VERSION 5.8 ;
BUSBITCHARS "[]" ;
DIVIDERCHAR "/" ;
UNITS
    DATABASE MICRONS 1000 ;
END UNITS

VIA simple_alu_via2_3_1600_480_1_5_320_320
  VIARULE M1M2_PR ;
  CUTSIZE 0.15 0.15 ;
  LAYERS met1 via met2 ;
  CUTSPACING 0.17 0.17 ;
  ENCLOSURE 0.085 0.165 0.055 0.085 ;
  ROWCOL 1 5 ;
END simple_alu_via2_3_1600_480_1_5_320_320

VIA simple_alu_via3_4_1600_480_1_4_400_400
  VIARULE M2M3_PR ;
  CUTSIZE 0.2 0.2 ;
  LAYERS met2 via2 met3 ;
  CUTSPACING 0.2 0.2 ;
  ENCLOSURE 0.04 0.085 0.065 0.065 ;
  ROWCOL 1 4 ;
END simple_alu_via3_4_1600_480_1_4_400_400

VIA simple_alu_via4_5_1600_480_1_4_400_400
  VIARULE M3M4_PR ;
  CUTSIZE 0.2 0.2 ;
  LAYERS met3 via3 met4 ;
  CUTSPACING 0.2 0.2 ;
  ENCLOSURE 0.09 0.06 0.1 0.065 ;
  ROWCOL 1 4 ;
END simple_alu_via4_5_1600_480_1_4_400_400

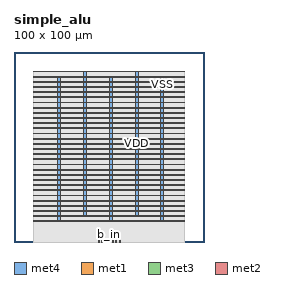
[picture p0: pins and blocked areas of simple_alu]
MACRO simple_alu
  FOREIGN simple_alu 0 0 ;
  CLASS BLOCK ;
  SIZE 100 BY 100 ;
  PIN VDD
    USE POWER ;
    DIRECTION INOUT ;
    PORT
      LAYER met4 ;
        RECT  63.72 13.36 65.32 90 ;
        RECT  36.52 13.36 38.12 90 ;
      LAYER met1 ;
        RECT  10.12 89.52 89.7 90 ;
        RECT  10.12 84.08 89.7 84.56 ;
        RECT  10.12 78.64 89.7 79.12 ;
        RECT  10.12 73.2 89.7 73.68 ;
        RECT  10.12 67.76 89.7 68.24 ;
        RECT  10.12 62.32 89.7 62.8 ;
        RECT  10.12 56.88 89.7 57.36 ;
        RECT  10.12 51.44 89.7 51.92 ;
        RECT  10.12 46 89.7 46.48 ;
        RECT  10.12 40.56 89.7 41.04 ;
        RECT  10.12 35.12 89.7 35.6 ;
        RECT  10.12 29.68 89.7 30.16 ;
        RECT  10.12 24.24 89.7 24.72 ;
        RECT  10.12 18.8 89.7 19.28 ;
        RECT  10.12 13.36 89.7 13.84 ;
      LAYER met3 ;
        RECT  63.73 89.595 65.31 89.925 ;
      VIA 64.52 89.76 simple_alu_via4_5_1600_480_1_4_400_400 ;
      LAYER met2 ;
        RECT  63.75 89.575 65.29 89.945 ;
      VIA 64.52 89.76 simple_alu_via3_4_1600_480_1_4_400_400 ;
      VIA 64.52 89.76 simple_alu_via2_3_1600_480_1_5_320_320 ;
      LAYER met3 ;
        RECT  63.73 84.155 65.31 84.485 ;
      VIA 64.52 84.32 simple_alu_via4_5_1600_480_1_4_400_400 ;
      LAYER met2 ;
        RECT  63.75 84.135 65.29 84.505 ;
      VIA 64.52 84.32 simple_alu_via3_4_1600_480_1_4_400_400 ;
      VIA 64.52 84.32 simple_alu_via2_3_1600_480_1_5_320_320 ;
      LAYER met3 ;
        RECT  63.73 78.715 65.31 79.045 ;
      VIA 64.52 78.88 simple_alu_via4_5_1600_480_1_4_400_400 ;
      LAYER met2 ;
        RECT  63.75 78.695 65.29 79.065 ;
      VIA 64.52 78.88 simple_alu_via3_4_1600_480_1_4_400_400 ;
      VIA 64.52 78.88 simple_alu_via2_3_1600_480_1_5_320_320 ;
      LAYER met3 ;
        RECT  63.73 73.275 65.31 73.605 ;
      VIA 64.52 73.44 simple_alu_via4_5_1600_480_1_4_400_400 ;
      LAYER met2 ;
        RECT  63.75 73.255 65.29 73.625 ;
      VIA 64.52 73.44 simple_alu_via3_4_1600_480_1_4_400_400 ;
      VIA 64.52 73.44 simple_alu_via2_3_1600_480_1_5_320_320 ;
      LAYER met3 ;
        RECT  63.73 67.835 65.31 68.165 ;
      VIA 64.52 68 simple_alu_via4_5_1600_480_1_4_400_400 ;
      LAYER met2 ;
        RECT  63.75 67.815 65.29 68.185 ;
      VIA 64.52 68 simple_alu_via3_4_1600_480_1_4_400_400 ;
      VIA 64.52 68 simple_alu_via2_3_1600_480_1_5_320_320 ;
      LAYER met3 ;
        RECT  63.73 62.395 65.31 62.725 ;
      VIA 64.52 62.56 simple_alu_via4_5_1600_480_1_4_400_400 ;
      LAYER met2 ;
        RECT  63.75 62.375 65.29 62.745 ;
      VIA 64.52 62.56 simple_alu_via3_4_1600_480_1_4_400_400 ;
      VIA 64.52 62.56 simple_alu_via2_3_1600_480_1_5_320_320 ;
      LAYER met3 ;
        RECT  63.73 56.955 65.31 57.285 ;
      VIA 64.52 57.12 simple_alu_via4_5_1600_480_1_4_400_400 ;
      LAYER met2 ;
        RECT  63.75 56.935 65.29 57.305 ;
      VIA 64.52 57.12 simple_alu_via3_4_1600_480_1_4_400_400 ;
      VIA 64.52 57.12 simple_alu_via2_3_1600_480_1_5_320_320 ;
      LAYER met3 ;
        RECT  63.73 51.515 65.31 51.845 ;
      VIA 64.52 51.68 simple_alu_via4_5_1600_480_1_4_400_400 ;
      LAYER met2 ;
        RECT  63.75 51.495 65.29 51.865 ;
      VIA 64.52 51.68 simple_alu_via3_4_1600_480_1_4_400_400 ;
      VIA 64.52 51.68 simple_alu_via2_3_1600_480_1_5_320_320 ;
      LAYER met3 ;
        RECT  63.73 46.075 65.31 46.405 ;
      VIA 64.52 46.24 simple_alu_via4_5_1600_480_1_4_400_400 ;
      LAYER met2 ;
        RECT  63.75 46.055 65.29 46.425 ;
      VIA 64.52 46.24 simple_alu_via3_4_1600_480_1_4_400_400 ;
      VIA 64.52 46.24 simple_alu_via2_3_1600_480_1_5_320_320 ;
      LAYER met3 ;
        RECT  63.73 40.635 65.31 40.965 ;
      VIA 64.52 40.8 simple_alu_via4_5_1600_480_1_4_400_400 ;
      LAYER met2 ;
        RECT  63.75 40.615 65.29 40.985 ;
      VIA 64.52 40.8 simple_alu_via3_4_1600_480_1_4_400_400 ;
      VIA 64.52 40.8 simple_alu_via2_3_1600_480_1_5_320_320 ;
      LAYER met3 ;
        RECT  63.73 35.195 65.31 35.525 ;
      VIA 64.52 35.36 simple_alu_via4_5_1600_480_1_4_400_400 ;
      LAYER met2 ;
        RECT  63.75 35.175 65.29 35.545 ;
      VIA 64.52 35.36 simple_alu_via3_4_1600_480_1_4_400_400 ;
      VIA 64.52 35.36 simple_alu_via2_3_1600_480_1_5_320_320 ;
      LAYER met3 ;
        RECT  63.73 29.755 65.31 30.085 ;
      VIA 64.52 29.92 simple_alu_via4_5_1600_480_1_4_400_400 ;
      LAYER met2 ;
        RECT  63.75 29.735 65.29 30.105 ;
      VIA 64.52 29.92 simple_alu_via3_4_1600_480_1_4_400_400 ;
      VIA 64.52 29.92 simple_alu_via2_3_1600_480_1_5_320_320 ;
      LAYER met3 ;
        RECT  63.73 24.315 65.31 24.645 ;
      VIA 64.52 24.48 simple_alu_via4_5_1600_480_1_4_400_400 ;
      LAYER met2 ;
        RECT  63.75 24.295 65.29 24.665 ;
      VIA 64.52 24.48 simple_alu_via3_4_1600_480_1_4_400_400 ;
      VIA 64.52 24.48 simple_alu_via2_3_1600_480_1_5_320_320 ;
      LAYER met3 ;
        RECT  63.73 18.875 65.31 19.205 ;
      VIA 64.52 19.04 simple_alu_via4_5_1600_480_1_4_400_400 ;
      LAYER met2 ;
        RECT  63.75 18.855 65.29 19.225 ;
      VIA 64.52 19.04 simple_alu_via3_4_1600_480_1_4_400_400 ;
      VIA 64.52 19.04 simple_alu_via2_3_1600_480_1_5_320_320 ;
      LAYER met3 ;
        RECT  63.73 13.435 65.31 13.765 ;
      VIA 64.52 13.6 simple_alu_via4_5_1600_480_1_4_400_400 ;
      LAYER met2 ;
        RECT  63.75 13.415 65.29 13.785 ;
      VIA 64.52 13.6 simple_alu_via3_4_1600_480_1_4_400_400 ;
      VIA 64.52 13.6 simple_alu_via2_3_1600_480_1_5_320_320 ;
      LAYER met3 ;
        RECT  36.53 89.595 38.11 89.925 ;
      VIA 37.32 89.76 simple_alu_via4_5_1600_480_1_4_400_400 ;
      LAYER met2 ;
        RECT  36.55 89.575 38.09 89.945 ;
      VIA 37.32 89.76 simple_alu_via3_4_1600_480_1_4_400_400 ;
      VIA 37.32 89.76 simple_alu_via2_3_1600_480_1_5_320_320 ;
      LAYER met3 ;
        RECT  36.53 84.155 38.11 84.485 ;
      VIA 37.32 84.32 simple_alu_via4_5_1600_480_1_4_400_400 ;
      LAYER met2 ;
        RECT  36.55 84.135 38.09 84.505 ;
      VIA 37.32 84.32 simple_alu_via3_4_1600_480_1_4_400_400 ;
      VIA 37.32 84.32 simple_alu_via2_3_1600_480_1_5_320_320 ;
      LAYER met3 ;
        RECT  36.53 78.715 38.11 79.045 ;
      VIA 37.32 78.88 simple_alu_via4_5_1600_480_1_4_400_400 ;
      LAYER met2 ;
        RECT  36.55 78.695 38.09 79.065 ;
      VIA 37.32 78.88 simple_alu_via3_4_1600_480_1_4_400_400 ;
      VIA 37.32 78.88 simple_alu_via2_3_1600_480_1_5_320_320 ;
      LAYER met3 ;
        RECT  36.53 73.275 38.11 73.605 ;
      VIA 37.32 73.44 simple_alu_via4_5_1600_480_1_4_400_400 ;
      LAYER met2 ;
        RECT  36.55 73.255 38.09 73.625 ;
      VIA 37.32 73.44 simple_alu_via3_4_1600_480_1_4_400_400 ;
      VIA 37.32 73.44 simple_alu_via2_3_1600_480_1_5_320_320 ;
      LAYER met3 ;
        RECT  36.53 67.835 38.11 68.165 ;
      VIA 37.32 68 simple_alu_via4_5_1600_480_1_4_400_400 ;
      LAYER met2 ;
        RECT  36.55 67.815 38.09 68.185 ;
      VIA 37.32 68 simple_alu_via3_4_1600_480_1_4_400_400 ;
      VIA 37.32 68 simple_alu_via2_3_1600_480_1_5_320_320 ;
      LAYER met3 ;
        RECT  36.53 62.395 38.11 62.725 ;
      VIA 37.32 62.56 simple_alu_via4_5_1600_480_1_4_400_400 ;
      LAYER met2 ;
        RECT  36.55 62.375 38.09 62.745 ;
      VIA 37.32 62.56 simple_alu_via3_4_1600_480_1_4_400_400 ;
      VIA 37.32 62.56 simple_alu_via2_3_1600_480_1_5_320_320 ;
      LAYER met3 ;
        RECT  36.53 56.955 38.11 57.285 ;
      VIA 37.32 57.12 simple_alu_via4_5_1600_480_1_4_400_400 ;
      LAYER met2 ;
        RECT  36.55 56.935 38.09 57.305 ;
      VIA 37.32 57.12 simple_alu_via3_4_1600_480_1_4_400_400 ;
      VIA 37.32 57.12 simple_alu_via2_3_1600_480_1_5_320_320 ;
      LAYER met3 ;
        RECT  36.53 51.515 38.11 51.845 ;
      VIA 37.32 51.68 simple_alu_via4_5_1600_480_1_4_400_400 ;
      LAYER met2 ;
        RECT  36.55 51.495 38.09 51.865 ;
      VIA 37.32 51.68 simple_alu_via3_4_1600_480_1_4_400_400 ;
      VIA 37.32 51.68 simple_alu_via2_3_1600_480_1_5_320_320 ;
      LAYER met3 ;
        RECT  36.53 46.075 38.11 46.405 ;
      VIA 37.32 46.24 simple_alu_via4_5_1600_480_1_4_400_400 ;
      LAYER met2 ;
        RECT  36.55 46.055 38.09 46.425 ;
      VIA 37.32 46.24 simple_alu_via3_4_1600_480_1_4_400_400 ;
      VIA 37.32 46.24 simple_alu_via2_3_1600_480_1_5_320_320 ;
      LAYER met3 ;
        RECT  36.53 40.635 38.11 40.965 ;
      VIA 37.32 40.8 simple_alu_via4_5_1600_480_1_4_400_400 ;
      LAYER met2 ;
        RECT  36.55 40.615 38.09 40.985 ;
      VIA 37.32 40.8 simple_alu_via3_4_1600_480_1_4_400_400 ;
      VIA 37.32 40.8 simple_alu_via2_3_1600_480_1_5_320_320 ;
      LAYER met3 ;
        RECT  36.53 35.195 38.11 35.525 ;
      VIA 37.32 35.36 simple_alu_via4_5_1600_480_1_4_400_400 ;
      LAYER met2 ;
        RECT  36.55 35.175 38.09 35.545 ;
      VIA 37.32 35.36 simple_alu_via3_4_1600_480_1_4_400_400 ;
      VIA 37.32 35.36 simple_alu_via2_3_1600_480_1_5_320_320 ;
      LAYER met3 ;
        RECT  36.53 29.755 38.11 30.085 ;
      VIA 37.32 29.92 simple_alu_via4_5_1600_480_1_4_400_400 ;
      LAYER met2 ;
        RECT  36.55 29.735 38.09 30.105 ;
      VIA 37.32 29.92 simple_alu_via3_4_1600_480_1_4_400_400 ;
      VIA 37.32 29.92 simple_alu_via2_3_1600_480_1_5_320_320 ;
      LAYER met3 ;
        RECT  36.53 24.315 38.11 24.645 ;
      VIA 37.32 24.48 simple_alu_via4_5_1600_480_1_4_400_400 ;
      LAYER met2 ;
        RECT  36.55 24.295 38.09 24.665 ;
      VIA 37.32 24.48 simple_alu_via3_4_1600_480_1_4_400_400 ;
      VIA 37.32 24.48 simple_alu_via2_3_1600_480_1_5_320_320 ;
      LAYER met3 ;
        RECT  36.53 18.875 38.11 19.205 ;
      VIA 37.32 19.04 simple_alu_via4_5_1600_480_1_4_400_400 ;
      LAYER met2 ;
        RECT  36.55 18.855 38.09 19.225 ;
      VIA 37.32 19.04 simple_alu_via3_4_1600_480_1_4_400_400 ;
      VIA 37.32 19.04 simple_alu_via2_3_1600_480_1_5_320_320 ;
      LAYER met3 ;
        RECT  36.53 13.435 38.11 13.765 ;
      VIA 37.32 13.6 simple_alu_via4_5_1600_480_1_4_400_400 ;
      LAYER met2 ;
        RECT  36.55 13.415 38.09 13.785 ;
      VIA 37.32 13.6 simple_alu_via3_4_1600_480_1_4_400_400 ;
      VIA 37.32 13.6 simple_alu_via2_3_1600_480_1_5_320_320 ;
    END
  END VDD
  PIN VSS
    USE GROUND ;
    DIRECTION INOUT ;
    PORT
      LAYER met4 ;
        RECT  77.32 10.64 78.92 87.28 ;
        RECT  50.12 10.64 51.72 87.28 ;
        RECT  22.92 10.64 24.52 87.28 ;
      LAYER met1 ;
        RECT  10.12 86.8 89.7 87.28 ;
        RECT  10.12 81.36 89.7 81.84 ;
        RECT  10.12 75.92 89.7 76.4 ;
        RECT  10.12 70.48 89.7 70.96 ;
        RECT  10.12 65.04 89.7 65.52 ;
        RECT  10.12 59.6 89.7 60.08 ;
        RECT  10.12 54.16 89.7 54.64 ;
        RECT  10.12 48.72 89.7 49.2 ;
        RECT  10.12 43.28 89.7 43.76 ;
        RECT  10.12 37.84 89.7 38.32 ;
        RECT  10.12 32.4 89.7 32.88 ;
        RECT  10.12 26.96 89.7 27.44 ;
        RECT  10.12 21.52 89.7 22 ;
        RECT  10.12 16.08 89.7 16.56 ;
        RECT  10.12 10.64 89.7 11.12 ;
      LAYER met3 ;
        RECT  77.33 86.875 78.91 87.205 ;
      VIA 78.12 87.04 simple_alu_via4_5_1600_480_1_4_400_400 ;
      LAYER met2 ;
        RECT  77.35 86.855 78.89 87.225 ;
      VIA 78.12 87.04 simple_alu_via3_4_1600_480_1_4_400_400 ;
      VIA 78.12 87.04 simple_alu_via2_3_1600_480_1_5_320_320 ;
      LAYER met3 ;
        RECT  77.33 81.435 78.91 81.765 ;
      VIA 78.12 81.6 simple_alu_via4_5_1600_480_1_4_400_400 ;
      LAYER met2 ;
        RECT  77.35 81.415 78.89 81.785 ;
      VIA 78.12 81.6 simple_alu_via3_4_1600_480_1_4_400_400 ;
      VIA 78.12 81.6 simple_alu_via2_3_1600_480_1_5_320_320 ;
      LAYER met3 ;
        RECT  77.33 75.995 78.91 76.325 ;
      VIA 78.12 76.16 simple_alu_via4_5_1600_480_1_4_400_400 ;
      LAYER met2 ;
        RECT  77.35 75.975 78.89 76.345 ;
      VIA 78.12 76.16 simple_alu_via3_4_1600_480_1_4_400_400 ;
      VIA 78.12 76.16 simple_alu_via2_3_1600_480_1_5_320_320 ;
      LAYER met3 ;
        RECT  77.33 70.555 78.91 70.885 ;
      VIA 78.12 70.72 simple_alu_via4_5_1600_480_1_4_400_400 ;
      LAYER met2 ;
        RECT  77.35 70.535 78.89 70.905 ;
      VIA 78.12 70.72 simple_alu_via3_4_1600_480_1_4_400_400 ;
      VIA 78.12 70.72 simple_alu_via2_3_1600_480_1_5_320_320 ;
      LAYER met3 ;
        RECT  77.33 65.115 78.91 65.445 ;
      VIA 78.12 65.28 simple_alu_via4_5_1600_480_1_4_400_400 ;
      LAYER met2 ;
        RECT  77.35 65.095 78.89 65.465 ;
      VIA 78.12 65.28 simple_alu_via3_4_1600_480_1_4_400_400 ;
      VIA 78.12 65.28 simple_alu_via2_3_1600_480_1_5_320_320 ;
      LAYER met3 ;
        RECT  77.33 59.675 78.91 60.005 ;
      VIA 78.12 59.84 simple_alu_via4_5_1600_480_1_4_400_400 ;
      LAYER met2 ;
        RECT  77.35 59.655 78.89 60.025 ;
      VIA 78.12 59.84 simple_alu_via3_4_1600_480_1_4_400_400 ;
      VIA 78.12 59.84 simple_alu_via2_3_1600_480_1_5_320_320 ;
      LAYER met3 ;
        RECT  77.33 54.235 78.91 54.565 ;
      VIA 78.12 54.4 simple_alu_via4_5_1600_480_1_4_400_400 ;
      LAYER met2 ;
        RECT  77.35 54.215 78.89 54.585 ;
      VIA 78.12 54.4 simple_alu_via3_4_1600_480_1_4_400_400 ;
      VIA 78.12 54.4 simple_alu_via2_3_1600_480_1_5_320_320 ;
      LAYER met3 ;
        RECT  77.33 48.795 78.91 49.125 ;
      VIA 78.12 48.96 simple_alu_via4_5_1600_480_1_4_400_400 ;
      LAYER met2 ;
        RECT  77.35 48.775 78.89 49.145 ;
      VIA 78.12 48.96 simple_alu_via3_4_1600_480_1_4_400_400 ;
      VIA 78.12 48.96 simple_alu_via2_3_1600_480_1_5_320_320 ;
      LAYER met3 ;
        RECT  77.33 43.355 78.91 43.685 ;
      VIA 78.12 43.52 simple_alu_via4_5_1600_480_1_4_400_400 ;
      LAYER met2 ;
        RECT  77.35 43.335 78.89 43.705 ;
      VIA 78.12 43.52 simple_alu_via3_4_1600_480_1_4_400_400 ;
      VIA 78.12 43.52 simple_alu_via2_3_1600_480_1_5_320_320 ;
      LAYER met3 ;
        RECT  77.33 37.915 78.91 38.245 ;
      VIA 78.12 38.08 simple_alu_via4_5_1600_480_1_4_400_400 ;
      LAYER met2 ;
        RECT  77.35 37.895 78.89 38.265 ;
      VIA 78.12 38.08 simple_alu_via3_4_1600_480_1_4_400_400 ;
      VIA 78.12 38.08 simple_alu_via2_3_1600_480_1_5_320_320 ;
      LAYER met3 ;
        RECT  77.33 32.475 78.91 32.805 ;
      VIA 78.12 32.64 simple_alu_via4_5_1600_480_1_4_400_400 ;
      LAYER met2 ;
        RECT  77.35 32.455 78.89 32.825 ;
      VIA 78.12 32.64 simple_alu_via3_4_1600_480_1_4_400_400 ;
      VIA 78.12 32.64 simple_alu_via2_3_1600_480_1_5_320_320 ;
      LAYER met3 ;
        RECT  77.33 27.035 78.91 27.365 ;
      VIA 78.12 27.2 simple_alu_via4_5_1600_480_1_4_400_400 ;
      LAYER met2 ;
        RECT  77.35 27.015 78.89 27.385 ;
      VIA 78.12 27.2 simple_alu_via3_4_1600_480_1_4_400_400 ;
      VIA 78.12 27.2 simple_alu_via2_3_1600_480_1_5_320_320 ;
      LAYER met3 ;
        RECT  77.33 21.595 78.91 21.925 ;
      VIA 78.12 21.76 simple_alu_via4_5_1600_480_1_4_400_400 ;
      LAYER met2 ;
        RECT  77.35 21.575 78.89 21.945 ;
      VIA 78.12 21.76 simple_alu_via3_4_1600_480_1_4_400_400 ;
      VIA 78.12 21.76 simple_alu_via2_3_1600_480_1_5_320_320 ;
      LAYER met3 ;
        RECT  77.33 16.155 78.91 16.485 ;
      VIA 78.12 16.32 simple_alu_via4_5_1600_480_1_4_400_400 ;
      LAYER met2 ;
        RECT  77.35 16.135 78.89 16.505 ;
      VIA 78.12 16.32 simple_alu_via3_4_1600_480_1_4_400_400 ;
      VIA 78.12 16.32 simple_alu_via2_3_1600_480_1_5_320_320 ;
      LAYER met3 ;
        RECT  77.33 10.715 78.91 11.045 ;
      VIA 78.12 10.88 simple_alu_via4_5_1600_480_1_4_400_400 ;
      LAYER met2 ;
        RECT  77.35 10.695 78.89 11.065 ;
      VIA 78.12 10.88 simple_alu_via3_4_1600_480_1_4_400_400 ;
      VIA 78.12 10.88 simple_alu_via2_3_1600_480_1_5_320_320 ;
      LAYER met3 ;
        RECT  50.13 86.875 51.71 87.205 ;
      VIA 50.92 87.04 simple_alu_via4_5_1600_480_1_4_400_400 ;
      LAYER met2 ;
        RECT  50.15 86.855 51.69 87.225 ;
      VIA 50.92 87.04 simple_alu_via3_4_1600_480_1_4_400_400 ;
      VIA 50.92 87.04 simple_alu_via2_3_1600_480_1_5_320_320 ;
      LAYER met3 ;
        RECT  50.13 81.435 51.71 81.765 ;
      VIA 50.92 81.6 simple_alu_via4_5_1600_480_1_4_400_400 ;
      LAYER met2 ;
        RECT  50.15 81.415 51.69 81.785 ;
      VIA 50.92 81.6 simple_alu_via3_4_1600_480_1_4_400_400 ;
      VIA 50.92 81.6 simple_alu_via2_3_1600_480_1_5_320_320 ;
      LAYER met3 ;
        RECT  50.13 75.995 51.71 76.325 ;
      VIA 50.92 76.16 simple_alu_via4_5_1600_480_1_4_400_400 ;
      LAYER met2 ;
        RECT  50.15 75.975 51.69 76.345 ;
      VIA 50.92 76.16 simple_alu_via3_4_1600_480_1_4_400_400 ;
      VIA 50.92 76.16 simple_alu_via2_3_1600_480_1_5_320_320 ;
      LAYER met3 ;
        RECT  50.13 70.555 51.71 70.885 ;
      VIA 50.92 70.72 simple_alu_via4_5_1600_480_1_4_400_400 ;
      LAYER met2 ;
        RECT  50.15 70.535 51.69 70.905 ;
      VIA 50.92 70.72 simple_alu_via3_4_1600_480_1_4_400_400 ;
      VIA 50.92 70.72 simple_alu_via2_3_1600_480_1_5_320_320 ;
      LAYER met3 ;
        RECT  50.13 65.115 51.71 65.445 ;
      VIA 50.92 65.28 simple_alu_via4_5_1600_480_1_4_400_400 ;
      LAYER met2 ;
        RECT  50.15 65.095 51.69 65.465 ;
      VIA 50.92 65.28 simple_alu_via3_4_1600_480_1_4_400_400 ;
      VIA 50.92 65.28 simple_alu_via2_3_1600_480_1_5_320_320 ;
      LAYER met3 ;
        RECT  50.13 59.675 51.71 60.005 ;
      VIA 50.92 59.84 simple_alu_via4_5_1600_480_1_4_400_400 ;
      LAYER met2 ;
        RECT  50.15 59.655 51.69 60.025 ;
      VIA 50.92 59.84 simple_alu_via3_4_1600_480_1_4_400_400 ;
      VIA 50.92 59.84 simple_alu_via2_3_1600_480_1_5_320_320 ;
      LAYER met3 ;
        RECT  50.13 54.235 51.71 54.565 ;
      VIA 50.92 54.4 simple_alu_via4_5_1600_480_1_4_400_400 ;
      LAYER met2 ;
        RECT  50.15 54.215 51.69 54.585 ;
      VIA 50.92 54.4 simple_alu_via3_4_1600_480_1_4_400_400 ;
      VIA 50.92 54.4 simple_alu_via2_3_1600_480_1_5_320_320 ;
      LAYER met3 ;
        RECT  50.13 48.795 51.71 49.125 ;
      VIA 50.92 48.96 simple_alu_via4_5_1600_480_1_4_400_400 ;
      LAYER met2 ;
        RECT  50.15 48.775 51.69 49.145 ;
      VIA 50.92 48.96 simple_alu_via3_4_1600_480_1_4_400_400 ;
      VIA 50.92 48.96 simple_alu_via2_3_1600_480_1_5_320_320 ;
      LAYER met3 ;
        RECT  50.13 43.355 51.71 43.685 ;
      VIA 50.92 43.52 simple_alu_via4_5_1600_480_1_4_400_400 ;
      LAYER met2 ;
        RECT  50.15 43.335 51.69 43.705 ;
      VIA 50.92 43.52 simple_alu_via3_4_1600_480_1_4_400_400 ;
      VIA 50.92 43.52 simple_alu_via2_3_1600_480_1_5_320_320 ;
      LAYER met3 ;
        RECT  50.13 37.915 51.71 38.245 ;
      VIA 50.92 38.08 simple_alu_via4_5_1600_480_1_4_400_400 ;
      LAYER met2 ;
        RECT  50.15 37.895 51.69 38.265 ;
      VIA 50.92 38.08 simple_alu_via3_4_1600_480_1_4_400_400 ;
      VIA 50.92 38.08 simple_alu_via2_3_1600_480_1_5_320_320 ;
      LAYER met3 ;
        RECT  50.13 32.475 51.71 32.805 ;
      VIA 50.92 32.64 simple_alu_via4_5_1600_480_1_4_400_400 ;
      LAYER met2 ;
        RECT  50.15 32.455 51.69 32.825 ;
      VIA 50.92 32.64 simple_alu_via3_4_1600_480_1_4_400_400 ;
      VIA 50.92 32.64 simple_alu_via2_3_1600_480_1_5_320_320 ;
      LAYER met3 ;
        RECT  50.13 27.035 51.71 27.365 ;
      VIA 50.92 27.2 simple_alu_via4_5_1600_480_1_4_400_400 ;
      LAYER met2 ;
        RECT  50.15 27.015 51.69 27.385 ;
      VIA 50.92 27.2 simple_alu_via3_4_1600_480_1_4_400_400 ;
      VIA 50.92 27.2 simple_alu_via2_3_1600_480_1_5_320_320 ;
      LAYER met3 ;
        RECT  50.13 21.595 51.71 21.925 ;
      VIA 50.92 21.76 simple_alu_via4_5_1600_480_1_4_400_400 ;
      LAYER met2 ;
        RECT  50.15 21.575 51.69 21.945 ;
      VIA 50.92 21.76 simple_alu_via3_4_1600_480_1_4_400_400 ;
      VIA 50.92 21.76 simple_alu_via2_3_1600_480_1_5_320_320 ;
      LAYER met3 ;
        RECT  50.13 16.155 51.71 16.485 ;
      VIA 50.92 16.32 simple_alu_via4_5_1600_480_1_4_400_400 ;
      LAYER met2 ;
        RECT  50.15 16.135 51.69 16.505 ;
      VIA 50.92 16.32 simple_alu_via3_4_1600_480_1_4_400_400 ;
      VIA 50.92 16.32 simple_alu_via2_3_1600_480_1_5_320_320 ;
      LAYER met3 ;
        RECT  50.13 10.715 51.71 11.045 ;
      VIA 50.92 10.88 simple_alu_via4_5_1600_480_1_4_400_400 ;
      LAYER met2 ;
        RECT  50.15 10.695 51.69 11.065 ;
      VIA 50.92 10.88 simple_alu_via3_4_1600_480_1_4_400_400 ;
      VIA 50.92 10.88 simple_alu_via2_3_1600_480_1_5_320_320 ;
      LAYER met3 ;
        RECT  22.93 86.875 24.51 87.205 ;
      VIA 23.72 87.04 simple_alu_via4_5_1600_480_1_4_400_400 ;
      LAYER met2 ;
        RECT  22.95 86.855 24.49 87.225 ;
      VIA 23.72 87.04 simple_alu_via3_4_1600_480_1_4_400_400 ;
      VIA 23.72 87.04 simple_alu_via2_3_1600_480_1_5_320_320 ;
      LAYER met3 ;
        RECT  22.93 81.435 24.51 81.765 ;
      VIA 23.72 81.6 simple_alu_via4_5_1600_480_1_4_400_400 ;
      LAYER met2 ;
        RECT  22.95 81.415 24.49 81.785 ;
      VIA 23.72 81.6 simple_alu_via3_4_1600_480_1_4_400_400 ;
      VIA 23.72 81.6 simple_alu_via2_3_1600_480_1_5_320_320 ;
      LAYER met3 ;
        RECT  22.93 75.995 24.51 76.325 ;
      VIA 23.72 76.16 simple_alu_via4_5_1600_480_1_4_400_400 ;
      LAYER met2 ;
        RECT  22.95 75.975 24.49 76.345 ;
      VIA 23.72 76.16 simple_alu_via3_4_1600_480_1_4_400_400 ;
      VIA 23.72 76.16 simple_alu_via2_3_1600_480_1_5_320_320 ;
      LAYER met3 ;
        RECT  22.93 70.555 24.51 70.885 ;
      VIA 23.72 70.72 simple_alu_via4_5_1600_480_1_4_400_400 ;
      LAYER met2 ;
        RECT  22.95 70.535 24.49 70.905 ;
      VIA 23.72 70.72 simple_alu_via3_4_1600_480_1_4_400_400 ;
      VIA 23.72 70.72 simple_alu_via2_3_1600_480_1_5_320_320 ;
      LAYER met3 ;
        RECT  22.93 65.115 24.51 65.445 ;
      VIA 23.72 65.28 simple_alu_via4_5_1600_480_1_4_400_400 ;
      LAYER met2 ;
        RECT  22.95 65.095 24.49 65.465 ;
      VIA 23.72 65.28 simple_alu_via3_4_1600_480_1_4_400_400 ;
      VIA 23.72 65.28 simple_alu_via2_3_1600_480_1_5_320_320 ;
      LAYER met3 ;
        RECT  22.93 59.675 24.51 60.005 ;
      VIA 23.72 59.84 simple_alu_via4_5_1600_480_1_4_400_400 ;
      LAYER met2 ;
        RECT  22.95 59.655 24.49 60.025 ;
      VIA 23.72 59.84 simple_alu_via3_4_1600_480_1_4_400_400 ;
      VIA 23.72 59.84 simple_alu_via2_3_1600_480_1_5_320_320 ;
      LAYER met3 ;
        RECT  22.93 54.235 24.51 54.565 ;
      VIA 23.72 54.4 simple_alu_via4_5_1600_480_1_4_400_400 ;
      LAYER met2 ;
        RECT  22.95 54.215 24.49 54.585 ;
      VIA 23.72 54.4 simple_alu_via3_4_1600_480_1_4_400_400 ;
      VIA 23.72 54.4 simple_alu_via2_3_1600_480_1_5_320_320 ;
      LAYER met3 ;
        RECT  22.93 48.795 24.51 49.125 ;
      VIA 23.72 48.96 simple_alu_via4_5_1600_480_1_4_400_400 ;
      LAYER met2 ;
        RECT  22.95 48.775 24.49 49.145 ;
      VIA 23.72 48.96 simple_alu_via3_4_1600_480_1_4_400_400 ;
      VIA 23.72 48.96 simple_alu_via2_3_1600_480_1_5_320_320 ;
      LAYER met3 ;
        RECT  22.93 43.355 24.51 43.685 ;
      VIA 23.72 43.52 simple_alu_via4_5_1600_480_1_4_400_400 ;
      LAYER met2 ;
        RECT  22.95 43.335 24.49 43.705 ;
      VIA 23.72 43.52 simple_alu_via3_4_1600_480_1_4_400_400 ;
      VIA 23.72 43.52 simple_alu_via2_3_1600_480_1_5_320_320 ;
      LAYER met3 ;
        RECT  22.93 37.915 24.51 38.245 ;
      VIA 23.72 38.08 simple_alu_via4_5_1600_480_1_4_400_400 ;
      LAYER met2 ;
        RECT  22.95 37.895 24.49 38.265 ;
      VIA 23.72 38.08 simple_alu_via3_4_1600_480_1_4_400_400 ;
      VIA 23.72 38.08 simple_alu_via2_3_1600_480_1_5_320_320 ;
      LAYER met3 ;
        RECT  22.93 32.475 24.51 32.805 ;
      VIA 23.72 32.64 simple_alu_via4_5_1600_480_1_4_400_400 ;
      LAYER met2 ;
        RECT  22.95 32.455 24.49 32.825 ;
      VIA 23.72 32.64 simple_alu_via3_4_1600_480_1_4_400_400 ;
      VIA 23.72 32.64 simple_alu_via2_3_1600_480_1_5_320_320 ;
      LAYER met3 ;
        RECT  22.93 27.035 24.51 27.365 ;
      VIA 23.72 27.2 simple_alu_via4_5_1600_480_1_4_400_400 ;
      LAYER met2 ;
        RECT  22.95 27.015 24.49 27.385 ;
      VIA 23.72 27.2 simple_alu_via3_4_1600_480_1_4_400_400 ;
      VIA 23.72 27.2 simple_alu_via2_3_1600_480_1_5_320_320 ;
      LAYER met3 ;
        RECT  22.93 21.595 24.51 21.925 ;
      VIA 23.72 21.76 simple_alu_via4_5_1600_480_1_4_400_400 ;
      LAYER met2 ;
        RECT  22.95 21.575 24.49 21.945 ;
      VIA 23.72 21.76 simple_alu_via3_4_1600_480_1_4_400_400 ;
      VIA 23.72 21.76 simple_alu_via2_3_1600_480_1_5_320_320 ;
      LAYER met3 ;
        RECT  22.93 16.155 24.51 16.485 ;
      VIA 23.72 16.32 simple_alu_via4_5_1600_480_1_4_400_400 ;
      LAYER met2 ;
        RECT  22.95 16.135 24.49 16.505 ;
      VIA 23.72 16.32 simple_alu_via3_4_1600_480_1_4_400_400 ;
      VIA 23.72 16.32 simple_alu_via2_3_1600_480_1_5_320_320 ;
      LAYER met3 ;
        RECT  22.93 10.715 24.51 11.045 ;
      VIA 23.72 10.88 simple_alu_via4_5_1600_480_1_4_400_400 ;
      LAYER met2 ;
        RECT  22.95 10.695 24.49 11.065 ;
      VIA 23.72 10.88 simple_alu_via3_4_1600_480_1_4_400_400 ;
      VIA 23.72 10.88 simple_alu_via2_3_1600_480_1_5_320_320 ;
    END
  END VSS
  PIN a_in
    DIRECTION INPUT ;
    USE SIGNAL ;
    PORT
      LAYER met4 ;
        RECT  55.51 0 55.81 0.8 ;
    END
  END a_in
  PIN b_in
    DIRECTION INPUT ;
    USE SIGNAL ;
    PORT
      LAYER met4 ;
        RECT  49.99 0 50.29 0.8 ;
    END
  END b_in
  PIN clk
    DIRECTION INPUT ;
    USE SIGNAL ;
    PORT
      LAYER met4 ;
        RECT  48.15 0 48.45 0.8 ;
    END
  END clk
  PIN flag_zero
    DIRECTION OUTPUT ;
    USE SIGNAL ;
    PORT
      LAYER met4 ;
        RECT  46.31 0 46.61 0.8 ;
    END
  END flag_zero
  PIN op_sel
    DIRECTION INPUT ;
    USE SIGNAL ;
    PORT
      LAYER met4 ;
        RECT  53.67 0 53.97 0.8 ;
    END
  END op_sel
  PIN res_out
    DIRECTION OUTPUT ;
    USE SIGNAL ;
    PORT
      LAYER met4 ;
        RECT  51.83 0 52.13 0.8 ;
    END
  END res_out
  PIN rst_n
    DIRECTION INPUT ;
    USE SIGNAL ;
    PORT
      LAYER met4 ;
        RECT  44.47 0 44.77 0.8 ;
    END
  END rst_n
  OBS
    LAYER nwell ;
     RECT  10.12 0 89.7 90 ;
    LAYER pwell ;
     RECT  10.12 0 89.7 90 ;
    LAYER li1 ;
     RECT  10.12 0 89.7 90 ;
    LAYER met1 ;
     RECT  10.12 0 89.7 90 ;
    LAYER met2 ;
     RECT  10.12 0 89.7 90 ;
    LAYER met3 ;
     RECT  10.12 0 89.7 90 ;
    LAYER met4 ;
     RECT  10.12 0 89.7 90 ;
  END
END simple_alu
END LIBRARY
